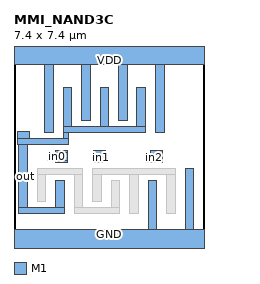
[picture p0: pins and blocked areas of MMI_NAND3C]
MACRO MMI_NAND3C
	CLASS CORE ;
	FOREIGN MMI_NAND3C 0 0 ;
	SIZE 7.4 BY 7.4 ;
	SYMMETRY X Y ;
	SITE CORE1 ;
	PIN out
		DIRECTION output ;
		USE SIGNAL ;
		PORT
			LAYER M1 ;
			RECT 1.91 4.49 2.25 6.02 ;
			LAYER M1 ;
			RECT 3.35 4.49 3.69 6.02 ;
			LAYER M1 ;
			RECT 4.79 4.49 5.13 6.02 ;
			LAYER M1 ;
			RECT 0.145 4.02 0.595 4.295 ;
			LAYER M1 ;
			RECT 1.91 4.26 5.13 4.49 ;
			LAYER M1 ;
			RECT 1.91 4.02 2.14 4.26 ;
			LAYER M1 ;
			RECT 0.145 3.79 2.14 4.02 ;
			LAYER M1 ;
			RECT 0.18 1.335 0.52 3.79 ;
			LAYER M1 ;
			RECT 1.62 1.335 1.96 2.385 ;
			LAYER M1 ;
			RECT 0.18 1.105 1.96 1.335 ;
		END
		AntennaDiffArea 4.8576 ;
	END out
	PIN in1
		DIRECTION input ;
		USE SIGNAL ;
		PORT
			LAYER M1 ;
			RECT 3.105 3.445 3.555 3.555 ;
			LAYER M1 ;
			RECT 3.105 3.105 3.66 3.445 ;
		END
		AntennaGateArea 1.656 ;
	END in1
	PIN GND
		DIRECTION inout ;
		USE GROUND ;
		PORT
			LAYER M1 ;
			RECT 5.22 0.5 5.56 2.385 ;
			LAYER M1 ;
			RECT 6.66 0.5 7 2.865 ;
			LAYER M1 ;
			RECT 0 -0.5 7.4 0.5 ;
		END
	END GND
	PIN in2
		DIRECTION input ;
		USE SIGNAL ;
		PORT
			LAYER M1 ;
			RECT 5.325 3.445 5.775 3.555 ;
			LAYER M1 ;
			RECT 5.11 3.105 5.775 3.445 ;
		END
		AntennaGateArea 1.656 ;
	END in2
	PIN VDD
		DIRECTION inout ;
		USE POWER ;
		PORT
			LAYER M1 ;
			RECT 0 6.9 7.4 7.9 ;
			LAYER M1 ;
			RECT 1.19 4.26 1.53 6.9 ;
			LAYER M1 ;
			RECT 2.63 4.74 2.97 6.9 ;
			LAYER M1 ;
			RECT 4.07 4.74 4.41 6.9 ;
			LAYER M1 ;
			RECT 5.51 4.26 5.85 6.9 ;
		END
	END VDD
	PIN in0
		DIRECTION input ;
		USE SIGNAL ;
		PORT
			LAYER M1 ;
			RECT 1.625 3.5 2.075 3.555 ;
			LAYER M1 ;
			RECT 1.31 3.16 2.075 3.5 ;
			LAYER M1 ;
			RECT 1.625 3.105 2.075 3.16 ;
		END
		AntennaGateArea 1.656 ;
	END in0
	OBS
		LAYER M1 ;
		RECT 0.9 2.635 2.68 2.865 ;
		LAYER M1 ;
		RECT 0.9 1.585 1.24 2.635 ;
		LAYER M1 ;
		RECT 2.34 1.335 2.68 2.635 ;
		LAYER M1 ;
		RECT 3.06 2.635 6.28 2.865 ;
		LAYER M1 ;
		RECT 3.06 1.585 3.4 2.635 ;
		LAYER M1 ;
		RECT 3.78 1.335 4.12 2.385 ;
		LAYER M1 ;
		RECT 2.34 1.105 4.12 1.335 ;
		LAYER M1 ;
		RECT 4.5 1.105 4.84 2.635 ;
		LAYER M1 ;
		RECT 5.94 1.105 6.28 2.635 ;
	END
END MMI_NAND3C
